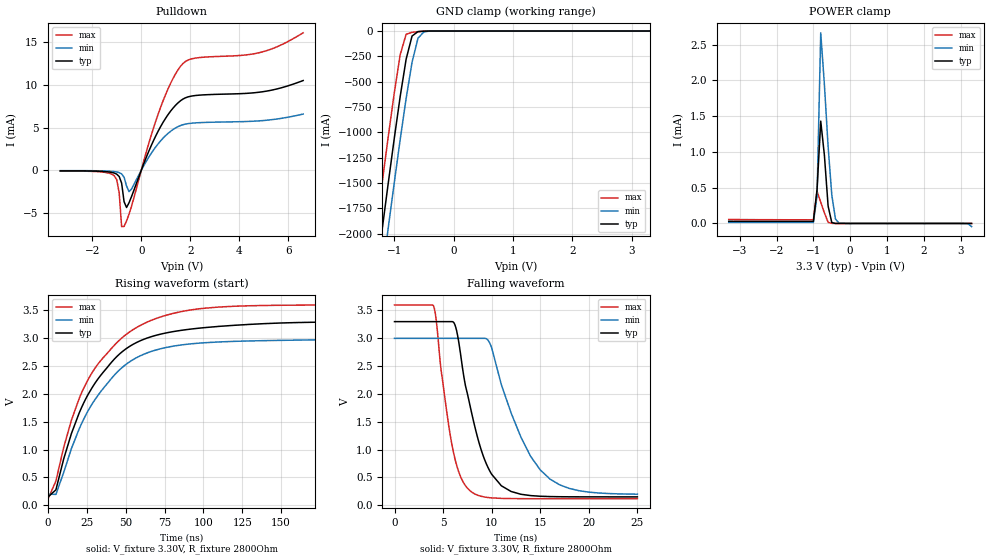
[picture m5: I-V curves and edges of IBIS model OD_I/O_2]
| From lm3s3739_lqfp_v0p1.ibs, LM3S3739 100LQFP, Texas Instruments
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[Model]   OD_I/O_2
Model_type   I/O_open_drain
Polarity   Inverting
Vinl = 1.26
Vinh = 2.04
Vmeas = 1.65
Rref = 2800
Vref = 3.3
| variable   typ   min   max
C_comp   9.739pF   9.739pF   9.803pF
[Model Spec]
Vinh+   1.91   1.78   2.04
Vinh-   1.90   1.76   2.03
Vinl+   1.40   1.27   1.54
Vinl-   1.39   1.26   1.53
| variable   typ   min   max
[Temperature Range]  25   85   -40
[Voltage Range]   3.3V   3.0V   3.6V
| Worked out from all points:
|   slope of the pulldown table from 0 to 0.495 V, typ, clamps not added: 143 ohm
|   GND clamp passes 1 mA (typ) near -0.48 V on its own axis
|   POWER clamp passes 1 mA (typ) near -0.71 V on its own axis
|   falling waveform, V_fixture 3.30V, R_fixture 2800Ohm: 20-80 % time 2.53ns typ, 3.91ns min, 1.72ns max; typ from 3.3 V to 0.149 V
|   rising waveform, V_fixture 3.30V, R_fixture 2800Ohm: 20-80 % time 34.6ns typ, 34.1ns min, 35.4ns max; typ from 0.149 V to 3.3 V
[Pulldown]
|  Voltage   I(typ)   I(min)   I(max)
-3.3V     -64.15uA   -36.41uA   -91.13uA
-1.1V     -318.3uA   -146.9uA   -641.8uA
-900mV    -721.3uA   -265.2uA   -2.635mA
-800mV    -1.498mA   -417.6uA   -6.598mA
-700mV    -3.678mA   -803.7uA   -6.582mA
-600mV    -4.358mA   -1.83mA    -5.933mA
-500mV    -3.814mA   -2.5mA     -5.165mA
700mV     4.654mA    3.152mA    6.687mA
1.2V      6.961mA    4.59mA     10.23mA
1.7V      8.361mA    5.354mA    12.53mA
4.9V      9.201mA    5.826mA    13.87mA
6.6V      10.54mA    6.604mA    16.13mA
[GND Clamp]
|  Voltage   I(typ)   I(min)   I(max)
-3.3V     -11.73A    -12.14A    -11.32A
-1.4V     -2.85A     -3.29A     -2.391A
-1.3V     -2.393A    -2.835A    -1.933A
-1.2V     -1.942A    -2.383A    -1.481A
-1.1V     -1.496A    -1.937A    -1.038A
-1V       -1.061A    -1.498A    -612.1mA
-900mV    -646.5mA   -1.071A    -233.9mA
-800mV    -278.2mA   -665.9mA   -32.18mA
-700mV    -49.12mA   -307.7mA   -12.49mA
-600mV    -5.764mA   -70.86mA   -6.504mA
-500mV    -1.206mA   -8.171mA   -2.256mA
3.3V      2.312nA    3.21uA     471pA
[POWER Clamp]
|  Voltage   I(typ)   I(min)   I(max)
-3.3V     29.71uA    15.87uA    54.94uA
-1V       27.67uA    14.78uA    51.22uA
-900mV    475.3uA    385.2uA    446.8uA
-800mV    1.43mA     2.664mA    297.3uA
-700mV    950.8uA    1.937mA    147.8uA
-600mV    244.5uA    1.079mA    15.75uA
-500mV    13.05uA    399.9uA    1.307uA
-400mV    328.8nA    62.11uA    58.57nA
-300mV    10.28nA    3.21uA     1.749nA
3.1V      1.297nA    -118nA     134.9pA
3.2V      1.2nA      -2.426uA   122pA
3.3V      -118pA     -43.75uA   108.5pA
[Ramp]
| variable   typ   min   max
dV/dt_f   1.89/2.53n   1.68/3.91n   2.09/1.72n
dV/dt_r   1.89/34.58n   1.68/34.09n   2.09/35.45n
R_load = 2800Ohm
[Falling Waveform]
V_fixture = 3.30V
V_fixture_min = 3.00V
V_fixture_max = 3.60V
R_fixture = 2800Ohm
|   Time   V(typ)   V(min)   V(max)
0s        3.3V       2.999V     3.6V
4ns       3.3V       2.999V     3.589V
5.4ns     3.3V       2.999V     1.651V
6.2ns     3.251V     2.999V     848.8mV
7.8ns     1.767V     2.999V     255.9mV
9.7ns     650.3mV    2.946V     136mV
11ns      348.4mV    2.165V     121.8mV
14ns      172.4mV    880.8mV    116.9mV
16ns      154.7mV    470.2mV    116.6mV
25ns      149mV      197.3mV    116.5mV
[Rising Waveform]
V_fixture = 3.30V
V_fixture_min = 3.00V
V_fixture_max = 3.60V
R_fixture = 2800Ohm
|   Time   V(typ)   V(min)   V(max)
0s        148.9mV    198.5mV    116.4mV
5ns       275.8mV    193.7mV    434.8mV
10ns      830.6mV    588.3mV    1.038V
15ns      1.289V     1.019V     1.529V
26ns      2.004V     1.711V     2.272V
44ns      2.665V     2.379V     2.915V
61ns      2.975V     2.706V     3.255V
83ns      3.131V     2.869V     3.463V
110ns     3.214V     2.934V     3.561V
250ns     3.298V     2.994V     3.599V
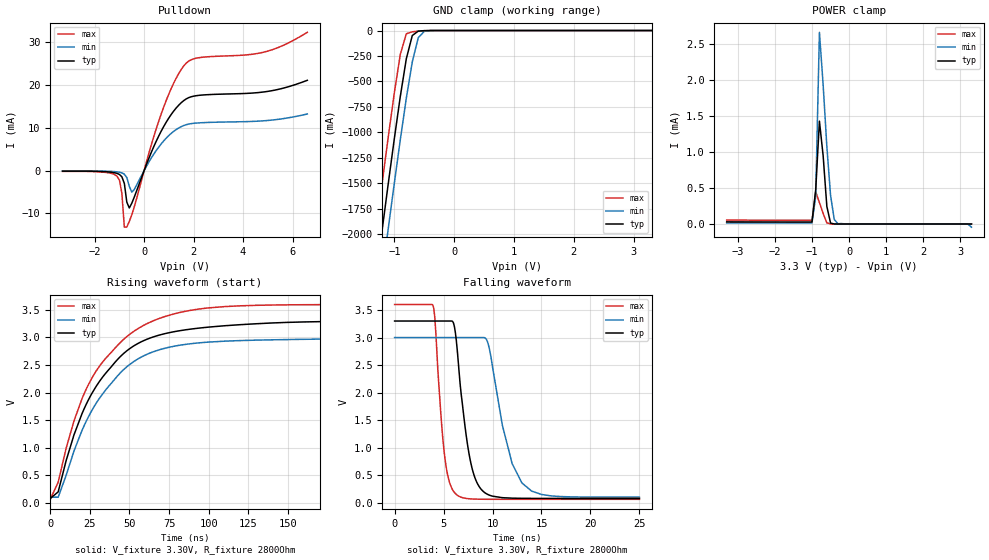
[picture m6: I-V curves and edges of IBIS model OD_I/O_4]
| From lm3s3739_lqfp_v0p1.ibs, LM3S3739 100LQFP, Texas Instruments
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[Model]   OD_I/O_4
Model_type   I/O_open_drain
Polarity   Inverting
Vinl = 1.26
Vinh = 2.04
Vmeas = 1.65
Rref = 2800
Vref = 3.3
| variable   typ   min   max
C_comp   9.739pF   9.739pF   9.803pF
[Model Spec]
Vinh+   1.91   1.78   2.04
Vinh-   1.90   1.76   2.03
Vinl+   1.40   1.27   1.54
Vinl-   1.39   1.26   1.53
| variable   typ   min   max
[Temperature Range]  25   85   -40
[Voltage Range]   3.3V   3.0V   3.6V
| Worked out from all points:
|   slope of the pulldown table from 0 to 0.495 V, typ, clamps not added: 71.5 ohm
|   GND clamp passes 1 mA (typ) near -0.48 V on its own axis
|   POWER clamp passes 1 mA (typ) near -0.71 V on its own axis
|   falling waveform, V_fixture 3.30V, R_fixture 2800Ohm: 20-80 % time 1.33ns typ, 2.04ns min, 898ps max; typ from 3.3 V to 0.075 V
|   rising waveform, V_fixture 3.30V, R_fixture 2800Ohm: 20-80 % time 34.6ns typ, 34.2ns min, 35.4ns max; typ from 0.075 V to 3.3 V
[Pulldown]
|  Voltage   I(typ)   I(min)   I(max)
-3.3V     -128.3uA   -72.81uA   -182.3uA
-1.1V     -636.5uA   -293.8uA   -1.284mA
-900mV    -1.443mA   -530.4uA   -5.27mA
-800mV    -2.996mA   -835.1uA   -13.2mA
-700mV    -7.355mA   -1.607mA   -13.16mA
-600mV    -8.716mA   -3.66mA    -11.87mA
-500mV    -7.628mA   -5mA       -10.33mA
700mV     9.309mA    6.304mA    13.37mA
1.2V      13.92mA    9.18mA     20.46mA
1.7V      16.72mA    10.71mA    25.07mA
4.9V      18.4mA     11.65mA    27.73mA
6.6V      21.07mA    13.21mA    32.27mA
[GND Clamp]
|  Voltage   I(typ)   I(min)   I(max)
-3.3V     -11.73A    -12.14A    -11.32A
-1.4V     -2.85A     -3.29A     -2.391A
-1.3V     -2.393A    -2.835A    -1.933A
-1.2V     -1.942A    -2.383A    -1.481A
-1.1V     -1.496A    -1.937A    -1.038A
-1V       -1.061A    -1.498A    -612.1mA
-900mV    -646.5mA   -1.071A    -233.9mA
-800mV    -278.2mA   -665.9mA   -32.18mA
-700mV    -49.12mA   -307.7mA   -12.49mA
-600mV    -5.764mA   -70.86mA   -6.504mA
-500mV    -1.206mA   -8.171mA   -2.256mA
3.3V      2.312nA    3.21uA     471pA
[POWER Clamp]
|  Voltage   I(typ)   I(min)   I(max)
-3.3V     29.71uA    15.87uA    54.94uA
-1V       27.67uA    14.78uA    51.22uA
-900mV    475.3uA    385.2uA    446.8uA
-800mV    1.43mA     2.664mA    297.3uA
-700mV    950.8uA    1.937mA    147.8uA
-600mV    244.5uA    1.079mA    15.75uA
-500mV    13.05uA    399.9uA    1.307uA
-400mV    328.8nA    62.11uA    58.57nA
-300mV    10.28nA    3.21uA     1.749nA
3.1V      1.297nA    -118nA     134.9pA
3.2V      1.2nA      -2.426uA   122pA
3.3V      -118pA     -43.75uA   108.5pA
[Ramp]
| variable   typ   min   max
dV/dt_f   1.93/1.33n   1.74/2.04n   2.12/0.90n
dV/dt_r   1.93/34.63n   1.74/34.23n   2.12/35.40n
R_load = 2800Ohm
[Falling Waveform]
V_fixture = 3.30V
V_fixture_min = 3.00V
V_fixture_max = 3.60V
R_fixture = 2800Ohm
|   Time   V(typ)   V(min)   V(max)
0s        3.3V       2.999V     3.6V
3.9ns     3.3V       2.999V     3.595V
5.1ns     3.3V       2.999V     860.7mV
6.3ns     2.949V     2.999V     147.2mV
7.6ns     887.2mV    2.999V     69.21mV
9.1ns     194.9mV    2.999V     59.98mV
9.7ns     133.1mV    2.777V     59.31mV
12ns      79.87mV    708.6mV    58.75mV
13ns      76.9mV     356.2mV    58.7mV
25ns      75.04mV    97.63mV    58.6mV
[Rising Waveform]
V_fixture = 3.30V
V_fixture_min = 3.00V
V_fixture_max = 3.60V
R_fixture = 2800Ohm
|   Time   V(typ)   V(min)   V(max)
0s        74.97mV    97.58mV    58.55mV
5ns       193.9mV    97.47mV    370.4mV
10ns      761.3mV    494.2mV    984.6mV
15ns      1.232V     940.5mV    1.486V
26ns      1.97V      1.661V     2.247V
44ns      2.646V     2.349V     2.902V
61ns      2.967V     2.693V     3.25V
83ns      3.129V     2.865V     3.462V
110ns     3.213V     2.933V     3.561V
250ns     3.298V     2.994V     3.599V
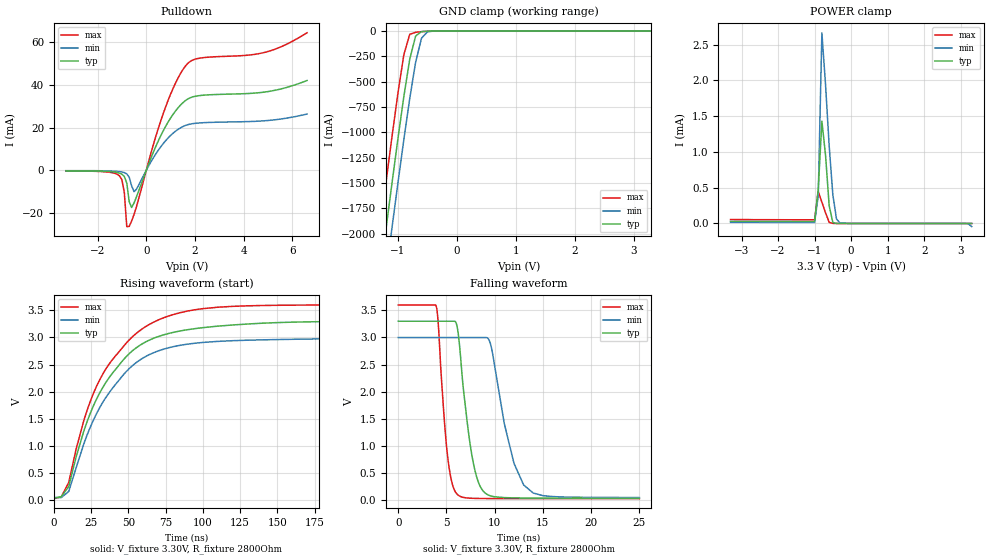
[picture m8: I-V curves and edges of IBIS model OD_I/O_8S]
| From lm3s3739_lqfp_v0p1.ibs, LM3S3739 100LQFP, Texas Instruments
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[Model]   OD_I/O_8S
Model_type   I/O_open_drain
Polarity   Inverting
Vinl = 1.26
Vinh = 2.04
Vmeas = 1.65
Rref = 2800
Vref = 3.3
| variable   typ   min   max
C_comp   9.739pF   9.739pF   9.803pF
[Model Spec]
Vinh+   1.91   1.78   2.04
Vinh-   1.90   1.76   2.03
Vinl+   1.40   1.27   1.54
Vinl-   1.39   1.26   1.53
| variable   typ   min   max
[Temperature Range]  25   85   -40
[Voltage Range]   3.3V   3.0V   3.6V
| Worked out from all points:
|   slope of the pulldown table from 0 to 0.495 V, typ, clamps not added: 35.8 ohm
|   GND clamp passes 1 mA (typ) near -0.48 V on its own axis
|   POWER clamp passes 1 mA (typ) near -0.71 V on its own axis
|   falling waveform, V_fixture 3.30V, R_fixture 2800Ohm: 20-80 % time 1.32ns typ, 2.04ns min, 892ps max; typ from 3.3 V to 0.038 V
|   rising waveform, V_fixture 3.30V, R_fixture 2800Ohm: 20-80 % time 34.6ns typ, 34.4ns min, 34.9ns max; typ from 0.038 V to 3.3 V
[Pulldown]
|  Voltage   I(typ)   I(min)   I(max)
-3.3V     -256.6uA   -145.6uA   -364.5uA
-1.1V     -1.273mA   -587.5uA   -2.567mA
-900mV    -2.885mA   -1.061mA   -10.54mA
-800mV    -5.993mA   -1.67mA    -26.39mA
-700mV    -14.71mA   -3.215mA   -26.33mA
-600mV    -17.43mA   -7.321mA   -23.73mA
-500mV    -15.26mA   -10mA      -20.66mA
700mV     18.62mA    12.61mA    26.75mA
1.2V      27.84mA    18.36mA    40.91mA
1.7V      33.44mA    21.41mA    50.13mA
4.9V      36.8mA     23.3mA     55.47mA
6.6V      42.15mA    26.42mA    64.53mA
[GND Clamp]
|  Voltage   I(typ)   I(min)   I(max)
-3.3V     -11.73A    -12.14A    -11.32A
-1.4V     -2.85A     -3.29A     -2.391A
-1.3V     -2.393A    -2.835A    -1.933A
-1.2V     -1.942A    -2.383A    -1.481A
-1.1V     -1.496A    -1.937A    -1.038A
-1V       -1.061A    -1.498A    -612.1mA
-900mV    -646.5mA   -1.071A    -233.9mA
-800mV    -278.2mA   -665.9mA   -32.18mA
-700mV    -49.12mA   -307.7mA   -12.49mA
-600mV    -5.764mA   -70.86mA   -6.504mA
-500mV    -1.206mA   -8.171mA   -2.256mA
3.3V      2.312nA    3.21uA     471pA
[POWER Clamp]
|  Voltage   I(typ)   I(min)   I(max)
-3.3V     29.71uA    15.87uA    54.94uA
-1V       27.67uA    14.78uA    51.22uA
-900mV    475.3uA    385.2uA    446.8uA
-800mV    1.43mA     2.664mA    297.3uA
-700mV    950.8uA    1.937mA    147.8uA
-600mV    244.5uA    1.079mA    15.75uA
-500mV    13.05uA    399.9uA    1.307uA
-400mV    328.8nA    62.11uA    58.57nA
-300mV    10.28nA    3.21uA     1.749nA
3.1V      1.297nA    -118nA     134.9pA
3.2V      1.2nA      -2.426uA   122pA
3.3V      -118pA     -43.75uA   108.5pA
[Ramp]
| variable   typ   min   max
dV/dt_f   1.96/1.32n   1.77/2.04n   2.14/0.89n
dV/dt_r   1.96/34.60n   1.77/34.37n   2.14/34.92n
R_load = 2800Ohm
[Falling Waveform]
V_fixture = 3.30V
V_fixture_min = 3.00V
V_fixture_max = 3.60V
R_fixture = 2800Ohm
|   Time   V(typ)   V(min)   V(max)
0s        3.3V       2.999V     3.6V
3.9ns     3.3V       2.999V     3.596V
5.1ns     3.3V       2.999V     842.8mV
6.2ns     3.103V     2.999V     97.23mV
7.6ns     870.1mV    2.999V     37.49mV
9ns       136mV      2.999V     32.55mV
9.7ns     75.46mV    2.782V     31.71mV
12ns      44.22mV    682.1mV    30.52mV
13ns      42.06mV    283.3mV    30.26mV
25ns      38mV       50.89mV    29.46mV
[Rising Waveform]
V_fixture = 3.30V
V_fixture_min = 3.00V
V_fixture_max = 3.60V
R_fixture = 2800Ohm
|   Time   V(typ)   V(min)   V(max)
0s        38.17mV    51.64mV    29.49mV
5ns       66.82mV    50.13mV    65.3mV
10ns      251.2mV    162.4mV    327.1mV
15ns      800.7mV    601.1mV    946.8mV
21ns      1.346V     1.106V     1.544V
33ns      2.085V     1.812V     2.331V
50ns      2.686V     2.41V      2.937V
66ns      2.974V     2.707V     3.268V
110ns     3.208V     2.927V     3.557V
250ns     3.298V     2.994V     3.599V
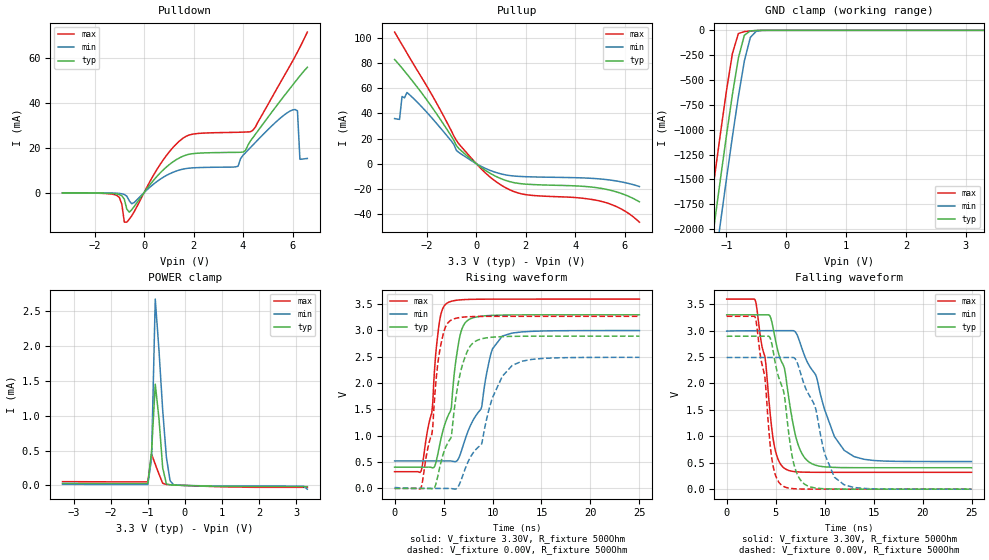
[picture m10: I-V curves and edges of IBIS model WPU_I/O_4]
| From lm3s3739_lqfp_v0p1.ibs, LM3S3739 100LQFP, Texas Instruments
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[Model]   WPU_I/O_4
Model_type   I/O
Vinl = 1.26
Vinh = 2.04
Vmeas = 1.65
| variable   typ   min   max
C_comp   9.739pF   9.739pF   9.803pF
[Model Spec]
Vinh+   1.91   1.78   2.04
Vinh-   1.90   1.76   2.03
Vinl+   1.40   1.27   1.54
Vinl-   1.39   1.26   1.53
| variable   typ   min   max
[Temperature Range]  25   85   -40
[Voltage Range]   3.3V   3.0V   3.6V
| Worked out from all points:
|   slope of the pulldown table from 0 to 0.495 V, typ, clamps not added: 71.5 ohm
|   slope of the pullup table from 0 to 0.495 V, typ, clamps not added: 71.7 ohm
|   GND clamp passes 1 mA (typ) near -0.48 V on its own axis
|   POWER clamp passes 1 mA (typ) near -0.71 V on its own axis
|   falling waveform, V_fixture 3.30V, R_fixture 500Ohm: 20-80 % time 1.98ns typ, 2.95ns min, 1.33ns max; typ from 3.3 V to 0.405 V
|   rising waveform, V_fixture 3.30V, R_fixture 500Ohm: 20-80 % time 1.71ns typ, 2.4ns min, 1.18ns max; typ from 0.405 V to 3.3 V
|   falling waveform, V_fixture 0.00V, R_fixture 500Ohm: 20-80 % time 1.7ns typ, 2.49ns min, 1.18ns max; typ from 2.89 V to 0 V
|   rising waveform, V_fixture 0.00V, R_fixture 500Ohm: 20-80 % time 2.03ns typ, 3.15ns min, 1.33ns max; typ from 0 V to 2.89 V
[Pulldown]
|  Voltage   I(typ)   I(min)   I(max)
-3.3V     -128.1uA   -72.7uA    -182uA
-1.1V     -635.5uA   -293.2uA   -1.281mA
-700mV    -7.352mA   -1.606mA   -13.14mA
-500mV    -7.614mA   -4.997mA   -10.31mA
700mV     9.325mA    6.314mA    13.4mA
1.6V      16.34mA    10.52mA    24.44mA
3.8V      17.93mA    11.75mA    26.87mA
4.4V      24.49mA    21.21mA    27.8mA
6V        47.81mA    36.8mA     58.52mA
6.2V      50.6mA     36.46mA    62.59mA
6.3V      51.97mA    14.83mA    64.73mA
6.6V      55.82mA    15.21mA    71.49mA
[Pullup]
|  Voltage   I(typ)   I(min)   I(max)
-3.3V     82.94mA    35.91mA    104.8mA
-3.1V     78.46mA    35.23mA    98.11mA
-3V       76.12mA    53.49mA    94.75mA
-2.9V     73.74mA    52.42mA    91.4mA
-2.8V     71.31mA    56.64mA    88.05mA
-1.6V     39.56mA    31.96mA    48.08mA
-800mV    14.31mA    10.46mA    18.42mA
700mV     -9.21mA    -6.417mA   -12.88mA
1.9V      -16.18mA   -10.35mA   -24.37mA
5.2V      -20.25mA   -12.6mA    -30.83mA
5.9V      -24.01mA   -14.69mA   -36.53mA
6.6V      -30.45mA   -18.28mA   -46.68mA
[GND Clamp]
|  Voltage   I(typ)   I(min)   I(max)
-3.3V     -11.73A    -12.14A    -11.32A
-1.4V     -2.85A     -3.29A     -2.391A
-1.3V     -2.393A    -2.835A    -1.933A
-1.2V     -1.942A    -2.383A    -1.481A
-1.1V     -1.496A    -1.937A    -1.038A
-1V       -1.061A    -1.498A    -612.1mA
-900mV    -646.5mA   -1.071A    -233.9mA
-800mV    -278.2mA   -665.9mA   -32.19mA
-700mV    -49.13mA   -307.7mA   -12.51mA
-600mV    -5.771mA   -70.87mA   -6.526mA
-500mV    -1.221mA   -8.174mA   -2.28mA
3.3V      2.312nA    7.026uA    -6.841uA
[POWER Clamp]
|  Voltage   I(typ)   I(min)   I(max)
-3.3V     29.71uA    15.87uA    54.94uA
-1V       27.67uA    14.78uA    51.22uA
-900mV    477.6uA    387.3uA    449.4uA
-800mV    1.453mA    2.675mA    305uA
-700mV    962.1uA    1.944mA    163.7uA
-600mV    254.6uA    1.086mA    31.4uA
-500mV    22.38uA    405.6uA    14.49uA
-400mV    7.783uA    67.02uA    10.49uA
-300mV    5.498uA    7.026uA    7.722uA
3.1V      -16.64uA   -9.952uA   -27.43uA
3.2V      -16.65uA   -12.25uA   -27.44uA
3.3V      -16.65uA   -53.27uA   -27.45uA
[Ramp]
| variable   typ   min   max
dV/dt_f   1.73/1.98n   1.48/2.95n   1.97/1.33n
dV/dt_r   1.74/2.03n   1.48/3.15n   1.96/1.33n
R_load = 500Ohm
[Falling Waveform]
V_fixture = 3.30V
V_fixture_min = 3.00V
V_fixture_max = 3.60V
R_fixture = 500Ohm
|   Time   V(typ)   V(min)   V(max)
0s        3.297V     2.99V      3.595V
2.9ns     3.297V     2.997V     3.584V
4ns       3.298V     2.998V     2.371V
4.8ns     2.99V      2.998V     887.6mV
5.9ns     2.286V     2.998V     394.2mV
7.1ns     961.8mV    2.952V     328.8mV
8.6ns     491.2mV    2.287V     319.7mV
11ns      411.2mV    995.1mV    318.6mV
13ns      406.3mV    617mV      318.5mV
25ns      405.4mV    522.4mV    318.5mV
[Rising Waveform]
V_fixture = 3.30V
V_fixture_min = 3.00V
V_fixture_max = 3.60V
R_fixture = 500Ohm
|   Time   V(typ)   V(min)   V(max)
0s        405.4mV    522.4mV    318.5mV
2.7ns     405.4mV    522.4mV    325.5mV
3.8ns     396.2mV    522.4mV    1.436V
4.6ns     825.6mV    522.4mV    3.19V
5.3ns     1.309V     522.4mV    3.512V
5.8ns     1.54V      520.4mV    3.555V
6.7ns     2.919V     646.8mV    3.582V
7.6ns     3.21V      1.134V     3.59V
11ns      3.293V     2.895V     3.596V
25ns      3.298V     2.999V     3.597V
[Falling Waveform]
V_fixture = 0.00V
V_fixture_min = 0.00V
V_fixture_max = 0.00V
R_fixture = 500Ohm
|   Time   V(typ)   V(min)   V(max)
0s        2.893V     2.49V      3.27V
2.9ns     2.893V     2.491V     3.258V
3.9ns     2.893V     2.491V     2.117V
4.6ns     2.755V     2.491V     588.5mV
5.7ns     1.917V     2.491V     64.29mV
6.8ns     521.4mV    2.49V      9.46mV
8.1ns     77.91mV    1.893V     1.44mV
10ns      7.517mV    669mV      209.9uV
12ns      1.014mV    81.45mV    73.19uV
25ns      18.39uV    38.9uV     11.44uV
[Rising Waveform]
V_fixture = 0.00V
V_fixture_min = 0.00V
V_fixture_max = 0.00V
R_fixture = 500Ohm
|   Time   V(typ)   V(min)   V(max)
0s        492.2uV    19.4mV     17.46uV
2.7ns     45.49uV    2.137mV    9.061mV
3.8ns     -8.433mV   973.8uV    1.029V
4.6ns     394.1mV    558.2uV    2.609V
5.7ns     943.7mV    269.7uV    3.188V
6.8ns     2.261V     163.8mV    3.25V
8.3ns     2.8V       740.2mV    3.266V
10ns      2.873V     1.728V     3.269V
12ns      2.889V     2.335V     3.269V
25ns      2.893V     2.49V      3.27V
